VERSION 5.8 ;
BUSBITCHARS "[]" ;
DIVIDERCHAR "/" ;
UNITS
    DATABASE MICRONS 1000 ;
END UNITS

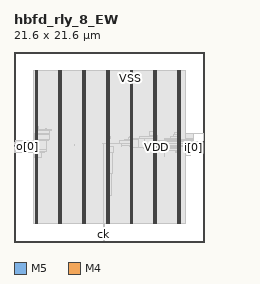
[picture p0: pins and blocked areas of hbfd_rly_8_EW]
MACRO hbfd_rly_8_EW
  FOREIGN hbfd_rly_8_EW 0 0 ;
  CLASS BLOCK ;
  SIZE 21.6 BY 21.6 ;
  PIN ck
    DIRECTION INPUT ;
    USE SIGNAL ;
    PORT
      LAYER M5 ;
        RECT  10.128 0 10.152 0.084 ;
    END
  END ck
  PIN i[0]
    DIRECTION INPUT ;
    USE SIGNAL ;
    PORT
      LAYER M4 ;
        RECT  21.516 10.704 21.6 10.728 ;
    END
  END i[0]
  PIN i[1]
    DIRECTION INPUT ;
    USE SIGNAL ;
    PORT
      LAYER M4 ;
        RECT  21.516 10.8 21.6 10.824 ;
    END
  END i[1]
  PIN i[2]
    DIRECTION INPUT ;
    USE SIGNAL ;
    PORT
      LAYER M4 ;
        RECT  21.516 10.896 21.6 10.92 ;
    END
  END i[2]
  PIN i[3]
    DIRECTION INPUT ;
    USE SIGNAL ;
    PORT
      LAYER M4 ;
        RECT  21.516 10.992 21.6 11.016 ;
    END
  END i[3]
  PIN i[4]
    DIRECTION INPUT ;
    USE SIGNAL ;
    PORT
      LAYER M4 ;
        RECT  21.516 11.088 21.6 11.112 ;
    END
  END i[4]
  PIN i[5]
    DIRECTION INPUT ;
    USE SIGNAL ;
    PORT
      LAYER M4 ;
        RECT  21.516 11.184 21.6 11.208 ;
    END
  END i[5]
  PIN i[6]
    DIRECTION INPUT ;
    USE SIGNAL ;
    PORT
      LAYER M4 ;
        RECT  21.516 11.28 21.6 11.304 ;
    END
  END i[6]
  PIN i[7]
    DIRECTION INPUT ;
    USE SIGNAL ;
    PORT
      LAYER M4 ;
        RECT  21.516 11.376 21.6 11.4 ;
    END
  END i[7]
  PIN o[0]
    DIRECTION OUTPUT ;
    USE SIGNAL ;
    PORT
      LAYER M4 ;
        RECT  0 10.896 0.084 10.92 ;
    END
  END o[0]
  PIN o[1]
    DIRECTION OUTPUT ;
    USE SIGNAL ;
    PORT
      LAYER M4 ;
        RECT  0 10.992 0.084 11.016 ;
    END
  END o[1]
  PIN o[2]
    DIRECTION OUTPUT ;
    USE SIGNAL ;
    PORT
      LAYER M4 ;
        RECT  0 11.088 0.084 11.112 ;
    END
  END o[2]
  PIN o[3]
    DIRECTION OUTPUT ;
    USE SIGNAL ;
    PORT
      LAYER M4 ;
        RECT  0 11.184 0.084 11.208 ;
    END
  END o[3]
  PIN o[4]
    DIRECTION OUTPUT ;
    USE SIGNAL ;
    PORT
      LAYER M4 ;
        RECT  0 11.28 0.084 11.304 ;
    END
  END o[4]
  PIN o[5]
    DIRECTION OUTPUT ;
    USE SIGNAL ;
    PORT
      LAYER M4 ;
        RECT  0 11.376 0.084 11.4 ;
    END
  END o[5]
  PIN o[6]
    DIRECTION OUTPUT ;
    USE SIGNAL ;
    PORT
      LAYER M4 ;
        RECT  0 11.472 0.084 11.496 ;
    END
  END o[6]
  PIN o[7]
    DIRECTION OUTPUT ;
    USE SIGNAL ;
    PORT
      LAYER M4 ;
        RECT  0 11.568 0.084 11.592 ;
    END
  END o[7]
  PIN rs
    DIRECTION INPUT ;
    USE SIGNAL ;
    PORT
      LAYER M5 ;
        RECT  10.224 0 10.248 0.084 ;
    END
  END rs
  PIN VDD
    DIRECTION INOUT ;
    USE POWER ;
    PORT
      LAYER M5 ;
        RECT  18.792 2.151 18.912 19.449 ;
        RECT  16.092 2.151 16.212 19.449 ;
        RECT  13.392 2.151 13.512 19.449 ;
        RECT  10.692 2.151 10.812 19.449 ;
        RECT  7.992 2.151 8.112 19.449 ;
        RECT  5.292 2.151 5.412 19.449 ;
        RECT  2.592 2.151 2.712 19.449 ;
    END
  END VDD
  PIN VSS
    DIRECTION INOUT ;
    USE GROUND ;
    PORT
      LAYER M5 ;
        RECT  18.6 2.137 18.72 19.463 ;
        RECT  15.9 2.137 16.02 19.463 ;
        RECT  13.2 2.137 13.32 19.463 ;
        RECT  10.5 2.137 10.62 19.463 ;
        RECT  7.8 2.137 7.92 19.463 ;
        RECT  5.1 2.137 5.22 19.463 ;
        RECT  2.4 2.137 2.52 19.463 ;
    END
  END VSS
  # OT_OBS_CLOSED layer=M5 d_um=1.536 added=0
  OBS
    LAYER RVTN ;
     RECT  2.16 2.16 19.44 2.295 ;
     RECT  2.16 2.565 19.44 2.835 ;
     RECT  2.16 3.105 19.44 3.375 ;
     RECT  2.16 3.645 19.44 3.915 ;
     RECT  2.16 4.185 19.44 4.455 ;
     RECT  2.16 4.725 19.44 4.995 ;
     RECT  2.16 5.265 19.44 5.535 ;
     RECT  2.16 5.805 19.44 6.075 ;
     RECT  2.16 6.345 19.44 6.615 ;
     RECT  2.16 6.885 19.44 7.155 ;
     RECT  2.16 7.425 19.44 7.695 ;
     RECT  2.16 7.965 19.44 8.235 ;
     RECT  2.16 8.505 19.44 8.775 ;
     RECT  2.16 9.045 19.44 9.315 ;
     RECT  2.16 9.585 19.44 9.855 ;
     RECT  2.16 10.125 19.44 10.395 ;
     RECT  2.16 10.665 19.44 10.935 ;
     RECT  2.16 11.205 19.44 11.475 ;
     RECT  2.16 11.745 19.44 12.015 ;
     RECT  2.16 12.285 19.44 12.555 ;
     RECT  2.16 12.825 19.44 13.095 ;
     RECT  2.16 13.365 19.44 13.635 ;
     RECT  2.16 13.905 19.44 14.175 ;
     RECT  2.16 14.445 19.44 14.715 ;
     RECT  2.16 14.985 19.44 15.255 ;
     RECT  2.16 15.525 19.44 15.795 ;
     RECT  2.16 16.065 19.44 16.335 ;
     RECT  2.16 16.605 19.44 16.875 ;
     RECT  2.16 17.145 19.44 17.415 ;
     RECT  2.16 17.685 19.44 17.955 ;
     RECT  2.16 18.225 19.44 18.495 ;
     RECT  2.16 18.765 19.44 19.035 ;
     RECT  2.16 19.305 19.44 19.44 ;
    LAYER RVTP ;
     RECT  2.16 2.295 19.44 2.565 ;
     RECT  2.16 2.835 19.44 3.105 ;
     RECT  2.16 3.375 19.44 3.645 ;
     RECT  2.16 3.915 19.44 4.185 ;
     RECT  2.16 4.455 19.44 4.725 ;
     RECT  2.16 4.995 19.44 5.265 ;
     RECT  2.16 5.535 19.44 5.805 ;
     RECT  2.16 6.075 19.44 6.345 ;
     RECT  2.16 6.615 19.44 6.885 ;
     RECT  2.16 7.155 19.44 7.425 ;
     RECT  2.16 7.695 19.44 7.965 ;
     RECT  2.16 8.235 19.44 8.505 ;
     RECT  2.16 8.775 19.44 9.045 ;
     RECT  2.16 9.315 19.44 9.585 ;
     RECT  2.16 9.855 19.44 10.125 ;
     RECT  2.16 10.395 19.44 10.665 ;
     RECT  2.16 10.935 19.44 11.205 ;
     RECT  2.16 11.475 19.44 11.745 ;
     RECT  2.16 12.015 19.44 12.285 ;
     RECT  2.16 12.555 19.44 12.825 ;
     RECT  2.16 13.095 19.44 13.365 ;
     RECT  2.16 13.635 19.44 13.905 ;
     RECT  2.16 14.175 19.44 14.445 ;
     RECT  2.16 14.715 19.44 14.985 ;
     RECT  2.16 15.255 19.44 15.525 ;
     RECT  2.16 15.795 19.44 16.065 ;
     RECT  2.16 16.335 19.44 16.605 ;
     RECT  2.16 16.875 19.44 17.145 ;
     RECT  2.16 17.415 19.44 17.685 ;
     RECT  2.16 17.955 19.44 18.225 ;
     RECT  2.16 18.495 19.44 18.765 ;
     RECT  2.16 19.035 19.44 19.305 ;
    LAYER M1 ;
     RECT  2.16 2.151 19.44 19.449 ;
    LAYER M2 ;
     RECT  0.103 10.206 2.16 10.224 ;
     RECT  2.16 2.151 19.44 19.449 ;
     RECT  19.44 9.864 19.967 10.728 ;
     RECT  19.967 10.71 20.003 10.728 ;
     RECT  19.967 9.864 20.039 9.882 ;
     RECT  19.44 11.718 20.435 12.312 ;
     RECT  20.435 12.294 21.515 12.312 ;
    LAYER M3 ;
     RECT  10.224 1.723 10.242 2.143 ;
     RECT  2.415 2.143 2.505 2.413 ;
     RECT  5.115 2.143 5.205 2.413 ;
     RECT  7.815 2.143 7.905 2.413 ;
     RECT  10.224 2.143 10.605 2.413 ;
     RECT  13.215 2.143 13.305 2.413 ;
     RECT  15.915 2.143 16.005 2.413 ;
     RECT  18.615 2.143 18.705 2.413 ;
     RECT  10.224 2.413 10.797 2.795 ;
     RECT  10.515 2.795 10.797 5.341 ;
     RECT  10.515 5.341 11.07 7.771 ;
     RECT  2.415 2.413 2.697 9.589 ;
     RECT  2.415 9.589 3.078 9.661 ;
     RECT  20.016 9.859 20.034 10.129 ;
     RECT  2.304 9.661 3.078 10.201 ;
     RECT  10.515 7.771 11.178 10.201 ;
     RECT  18.615 2.413 18.897 10.201 ;
     RECT  2.304 10.201 3.438 10.291 ;
     RECT  17.064 9.751 17.082 10.291 ;
     RECT  18.396 10.201 18.897 10.291 ;
     RECT  2.304 10.291 3.474 10.327 ;
     RECT  15.915 2.413 16.197 10.327 ;
     RECT  16.992 10.291 17.082 10.327 ;
     RECT  16.956 10.327 17.37 10.357 ;
     RECT  15.696 10.327 16.197 10.399 ;
     RECT  16.956 10.357 17.442 10.399 ;
     RECT  18.396 10.291 18.954 10.399 ;
     RECT  15.696 10.399 17.442 10.435 ;
     RECT  18.18 10.399 18.954 10.435 ;
     RECT  2.304 10.327 3.726 10.499 ;
     RECT  14.94 10.291 14.958 10.597 ;
     RECT  15.696 10.435 18.954 10.597 ;
     RECT  14.94 10.597 18.954 10.669 ;
     RECT  14.76 10.669 18.954 10.705 ;
     RECT  14.544 10.705 18.954 10.831 ;
     RECT  13.215 2.413 13.497 10.867 ;
     RECT  10.515 10.201 11.358 10.895 ;
     RECT  13.176 10.867 13.497 10.903 ;
     RECT  14.292 10.831 18.954 10.903 ;
     RECT  19.944 10.129 20.034 10.903 ;
     RECT  0.108 10.201 0.126 10.925 ;
     RECT  12.24 10.867 12.258 10.939 ;
     RECT  13.176 10.903 13.554 10.939 ;
     RECT  14.292 10.903 20.034 10.939 ;
     RECT  10.515 10.895 10.854 11.003 ;
     RECT  6.84 10.939 6.858 11.039 ;
     RECT  12.24 10.939 20.034 11.209 ;
     RECT  12.06 11.209 20.034 11.371 ;
     RECT  12.06 11.371 20.43 11.507 ;
     RECT  2.304 10.499 3.69 11.515 ;
     RECT  12.06 11.507 16.362 11.549 ;
     RECT  17.1 11.507 20.43 11.669 ;
     RECT  2.304 11.515 3.942 11.677 ;
     RECT  12.528 11.549 16.362 11.705 ;
     RECT  19.908 11.669 20.43 11.741 ;
     RECT  19.908 11.741 19.926 11.777 ;
     RECT  17.1 11.669 18.897 11.813 ;
     RECT  10.515 11.003 10.797 11.821 ;
     RECT  13.068 11.705 13.497 11.849 ;
     RECT  10.515 11.821 10.926 11.939 ;
     RECT  13.14 11.849 13.497 11.939 ;
     RECT  14.256 11.705 16.362 11.939 ;
     RECT  17.82 11.813 18.897 11.939 ;
     RECT  15.408 11.939 16.362 12.119 ;
     RECT  2.304 11.677 4.05 12.209 ;
     RECT  18.108 11.939 18.897 12.209 ;
     RECT  21.492 11.083 21.51 12.317 ;
     RECT  2.34 12.209 4.05 12.389 ;
     RECT  18.216 12.209 18.897 12.479 ;
     RECT  15.408 12.119 16.197 12.551 ;
     RECT  2.415 12.389 4.05 12.631 ;
     RECT  2.415 12.631 4.23 12.749 ;
     RECT  3.636 12.749 4.23 12.785 ;
     RECT  3.636 12.785 3.726 12.857 ;
     RECT  3.636 12.857 3.654 12.893 ;
     RECT  2.415 12.749 2.826 13.091 ;
     RECT  2.415 13.091 2.697 19.187 ;
     RECT  5.115 2.413 5.397 19.187 ;
     RECT  7.815 2.413 8.097 19.187 ;
     RECT  10.515 11.939 10.797 19.187 ;
     RECT  13.215 11.939 13.497 19.187 ;
     RECT  15.915 12.551 16.197 19.187 ;
     RECT  18.615 12.479 18.897 19.187 ;
     RECT  2.415 19.187 2.505 19.457 ;
     RECT  5.115 19.187 5.205 19.457 ;
     RECT  7.815 19.187 7.905 19.457 ;
     RECT  10.515 19.187 10.605 19.457 ;
     RECT  13.215 19.187 13.305 19.457 ;
     RECT  15.915 19.187 16.005 19.457 ;
     RECT  18.615 19.187 18.705 19.457 ;
    LAYER M4 ;
     RECT  0.06 10.896 0.137 11.592 ;
     RECT  0.137 10.992 2.408 11.592 ;
     RECT  2.408 2.148 2.512 19.452 ;
     RECT  2.512 2.418 2.704 19.182 ;
     RECT  2.704 11.472 2.765 11.496 ;
     RECT  5.108 2.148 5.212 19.452 ;
     RECT  5.212 2.418 5.404 19.182 ;
     RECT  7.808 2.148 7.912 19.452 ;
     RECT  7.912 2.418 8.104 19.182 ;
     RECT  10.213 1.728 10.297 1.752 ;
     RECT  10.117 11.184 10.508 11.208 ;
     RECT  10.508 2.148 10.612 19.452 ;
     RECT  10.612 2.418 10.804 19.182 ;
     RECT  10.804 11.184 12.049 11.208 ;
     RECT  12.049 11.184 13.208 11.544 ;
     RECT  13.208 2.148 13.312 19.452 ;
     RECT  13.312 2.418 13.504 19.182 ;
     RECT  13.504 10.704 14.789 11.736 ;
     RECT  14.789 11.184 15.908 11.736 ;
     RECT  15.908 2.148 16.012 19.452 ;
     RECT  16.012 2.418 16.204 19.182 ;
     RECT  16.204 10.368 16.733 11.496 ;
     RECT  16.733 10.368 17.309 10.824 ;
     RECT  17.309 10.368 17.453 10.392 ;
     RECT  18.421 10.704 18.608 10.728 ;
     RECT  18.608 2.148 18.712 19.452 ;
     RECT  18.712 2.418 18.904 19.182 ;
     RECT  18.904 10.992 19.897 11.208 ;
     RECT  19.897 10.992 19.933 11.304 ;
     RECT  19.933 10.704 20.401 11.304 ;
     RECT  20.401 10.704 21.564 11.4 ;
    LAYER M5 ;
     RECT  10.128 0.016 10.248 2.137 ;
     RECT  2.4 2.137 2.52 2.151 ;
     RECT  5.1 2.137 5.22 2.151 ;
     RECT  7.8 2.137 7.92 2.151 ;
     RECT  10.128 2.137 10.62 2.151 ;
     RECT  13.2 2.137 13.32 2.151 ;
     RECT  15.9 2.137 16.02 2.151 ;
     RECT  18.6 2.137 18.72 2.151 ;
     RECT  13.2 2.151 13.512 10.693 ;
     RECT  10.128 2.151 10.812 11.219 ;
     RECT  13.2 10.693 14.184 11.651 ;
     RECT  2.4 2.151 2.712 19.449 ;
     RECT  5.1 2.151 5.412 19.449 ;
     RECT  7.8 2.151 8.112 19.449 ;
     RECT  10.5 11.219 10.812 19.449 ;
     RECT  13.2 11.651 13.512 19.449 ;
     RECT  15.9 2.151 16.212 19.449 ;
     RECT  18.6 2.151 18.912 19.449 ;
     RECT  2.4 19.449 2.52 19.463 ;
     RECT  5.1 19.449 5.22 19.463 ;
     RECT  7.8 19.449 7.92 19.463 ;
     RECT  10.5 19.449 10.62 19.463 ;
     RECT  13.2 19.449 13.32 19.463 ;
     RECT  15.9 19.449 16.02 19.463 ;
     RECT  18.6 19.449 18.72 19.463 ;
  END
END hbfd_rly_8_EW
END LIBRARY
